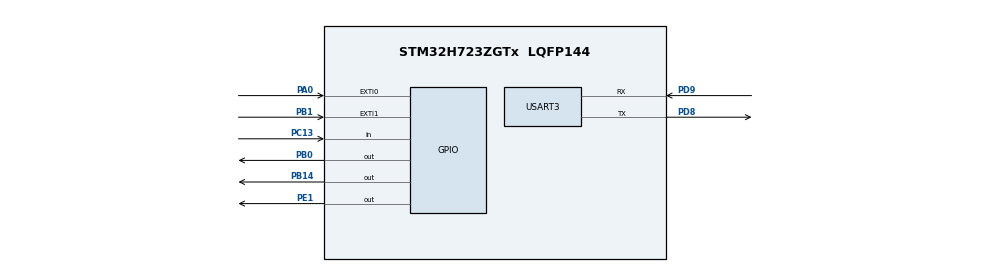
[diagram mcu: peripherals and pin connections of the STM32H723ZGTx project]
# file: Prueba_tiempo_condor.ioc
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CORTEX_M7.default_mode_Activation=1
Mcu.Family=STM32H7
Mcu.Name=STM32H723ZGTx
Mcu.Package=LQFP144
NUCLEO-H723ZG.BUTTON=1
NUCLEO-H723ZG.LD1=true
NUCLEO-H723ZG.LD2=true
NUCLEO-H723ZG.LD3=true
NUCLEO-H723ZG.VCP=false
NVIC.EXTI15_10_IRQn=true\:0\:0\:false\:false\:true\:false\:true\:true
NVIC.PriorityGroup=NVIC_PRIORITYGROUP_4
PA0.Signal=GPXTI0
PA13(JTMS/SWDIO).GPIO_Label=SWDIO
PA13(JTMS/SWDIO).Signal=DEBUG_JTMS-SWDIO
PA14(JTCK/SWCLK).GPIO_Label=SWCLK
PA14(JTCK/SWCLK).Signal=DEBUG_JTCK-SWCLK
PB0.Signal=GPIO_Output
PB1.Signal=GPXTI1
PB14.Signal=GPIO_Output
PC13.Signal=GPIO_Input
PC14-OSC32_IN.Signal=RCC_OSC32_IN
PC15-OSC32_OUT.Signal=RCC_OSC32_OUT
PD8.Mode=Asynchronous
PD8.Signal=USART3_TX
PD9.Mode=Asynchronous
PD9.Signal=USART3_RX
PE1.Signal=GPIO_Output
ProjectManager.HeapSize=0x200
ProjectManager.StackSize=0x400
ProjectManager.TargetToolchain=STM32CubeIDE
RCC.ADCFreq_Value=152000000
RCC.APB1Freq_Value=137500000
RCC.APB2Freq_Value=137500000
RCC.APB3Freq_Value=137500000
RCC.APB4Freq_Value=137500000
RCC.CortexFreq_Value=550000000
RCC.D1PPRE=RCC_APB3_DIV2
RCC.D2PPRE1=RCC_APB1_DIV2
RCC.D2PPRE2=RCC_APB2_DIV2
RCC.D3PPRE=RCC_APB4_DIV2
RCC.DIVM1=8
RCC.DIVM2=1
RCC.DIVN1=275
RCC.DIVN2=19
RCC.DIVP1=1
RCC.DIVQ1=4
RCC.HCLKFreq_Value=275000000
RCC.HPRE=RCC_HCLK_DIV2
RCC.HSE_VALUE=8000000
RCC.HSIDiv=RCC_PLLSAIDIVR_4
RCC.SYSCLKFreq_VALUE=550000000
RCC.SYSCLKSource=RCC_SYSCLKSOURCE_PLLCLK
RCC.USBCLockSelection=RCC_USBCLKSOURCE_HSI48
RCC.USBFreq_Value=48000000
USART3.VirtualMode-Asynchronous=VM_ASYNC
VP_MEMORYMAP_VS_MEMORYMAP.Mode=CurAppReg
VP_NUCLEO-H723ZG_VS_BSP_COMMON.Mode=COMMON
board=NUCLEO-H723ZG

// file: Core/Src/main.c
/* USER CODE BEGIN Header */
/**
  ******************************************************************************
  * @file           : main.c
  * @brief          : Main program body
  ******************************************************************************
  * @attention
  *
  * Copyright (c) 2025 STMicroelectronics.
  * All rights reserved.
  *
  * This software is licensed under terms that can be found in the LICENSE file
  * in the root directory of this software component.
  * If no LICENSE file comes with this software, it is provided AS-IS.
  *
  ******************************************************************************
  */
/* USER CODE END Header */
#include "main.h"

/* USER CODE BEGIN Includes */
#include <stdio.h>
#include <stdlib.h>
/* USER CODE END Includes */

/* USER CODE BEGIN PD */
#define PUTCHAR_PROTOTYPE       int __io_putchar(int ch)
/* USER CODE END PD */

UART_HandleTypeDef huart3;

void SystemClock_Config(void);
static void MPU_Config(void);
static void MX_GPIO_Init(void);
static void MX_USART3_UART_Init(void);

/* USER CODE BEGIN 0 */
void iniciar_DWT(void)
{
	// Habilitar DWT
	CoreDebug->DEMCR |= CoreDebug_DEMCR_TRCENA_Msk;
	DWT->CYCCNT = 0;
	DWT->CTRL |= DWT_CTRL_CYCCNTENA_Msk;
}

// MEDICIÓN DE LOS PRINT (SE PASA EL NÚMERO DE VECES QUE SE QUIERE REALIZAR LA OPERACIÓN COMO PARÁMETRO)
void test_printeo_caracter(uint32_t iteraciones)
{
    volatile uint32_t inicio, fin, ciclos, tiempo_ns;
    volatile uint32_t tiempos[iteraciones];
    volatile uint32_t max_value = 0;
    volatile uint32_t min_value = 4294967295;
    volatile uint32_t sum_value = 0;
    volatile uint32_t tiempo_medio;

    volatile uint32_t counter = 0;

    while (counter < iteraciones)
    {
        DWT->CYCCNT = 0;
        inicio = DWT->CYCCNT;
        printf("a\n");
        fin = DWT->CYCCNT;

        ciclos = fin - inicio;
        tiempo_ns = (ciclos * (1e9f / SystemCoreClock));

        tiempos[counter] = tiempo_ns;

        counter++;
    }

    // Obtener el valor máximo, mínimo y promedio entre todos los tiempos
    for (uint32_t i=0; i<=counter; i++)
    {
        if (tiempos[i] > max_value)
        {
            max_value = tiempos[i];
        }
        if (tiempos[i] < min_value)
        {
            min_value = tiempos[i];
        }

        sum_value += tiempos[i];

    }

    tiempo_medio = sum_value/iteraciones;

    printf("Tiempo promedio printf(): %lu ns\r\n\r\n", tiempo_medio);
    printf("Tiempo máximo printf(): %lu ns\r\n\r\n", max_value);
    printf("Tiempo mínimo printf(): %lu ns\r\n\r\n", min_value);
}

void test_printeo_multiples_caracteres(uint32_t iteraciones)
{
    volatile uint32_t inicio, fin, ciclos, tiempo_ns;
    volatile uint32_t tiempos[iteraciones];
    volatile uint32_t max_value = 0;
    volatile uint32_t min_value = 4294967295;
    volatile uint32_t sum_value = 0;
    volatile uint32_t tiempo_medio;

    volatile uint32_t counter = 0;

    while (counter < iteraciones)
    {
        DWT->CYCCNT = 0;
        inicio = DWT->CYCCNT;
        printf("[TEST] Printf simple.\n");
        fin = DWT->CYCCNT;

        ciclos = fin - inicio;
        tiempo_ns = (ciclos * (1e9f / SystemCoreClock));

        tiempos[counter] = tiempo_ns;

        counter++;
    }

    for (uint32_t i=0; i<=counter; i++)
    {
        if (tiempos[i] > max_value)
        {
            max_value = tiempos[i];
        }
        if (tiempos[i] < min_value)
        {
            min_value = tiempos[i];
        }

        sum_value += tiempos[i];

    }

    tiempo_medio = sum_value/iteraciones;

    printf("Tiempo promedio printf() múltiples caractéres: %lu ns\r\n\r\n", tiempo_medio);
    printf("Tiempo máximo printf() múltiples caractéres: %lu ns\r\n\r\n", max_value);
    printf("Tiempo mínimo printf() múltiples caractéres: %lu ns\r\n\r\n", min_value);
}

// MEDICIÓN DE LAS ASIGNACIONES SIMPLES
void test_asignaciones_8bits(uint32_t iteraciones)
{
    volatile uint32_t inicio, fin, ciclos, tiempo_ns;
    volatile uint32_t tiempos[iteraciones];
    volatile uint32_t max_value = 0;
    volatile uint32_t min_value = 4294967295;
    volatile uint32_t sum_value = 0;
    volatile uint32_t tiempo_medio;

    volatile uint32_t counter = 0;

    volatile uint8_t asignacion;

    while (counter < iteraciones)
    {
        DWT->CYCCNT = 0;
        inicio = DWT->CYCCNT;
        asignacion = rand() & 0xFF;
        fin = DWT->CYCCNT;

        ciclos = fin - inicio;
        tiempo_ns = (ciclos * (1e9f / SystemCoreClock));

        tiempos[counter] = tiempo_ns;

        counter++;
    }

    for (uint32_t i=0; i<=counter; i++)
    {
        if (tiempos[i] > max_value)
        {
            max_value = tiempos[i];
        }
        if (tiempos[i] < min_value)
        {
            min_value = tiempos[i];
        }

        sum_value += tiempos[i];

    }

    tiempo_medio = sum_value/iteraciones;

    printf("Tiempo promedio asignación 8bits: %lu ns\r\n\r\n", tiempo_medio);
    printf("Tiempo máximo asignación 8bits: %lu ns\r\n\r\n", max_value);
    printf("Tiempo mínimo asignación 8bits: %lu ns\r\n\r\n", min_value);

}

void test_asignaciones_16bits(uint32_t iteraciones)
{
    volatile uint32_t inicio, fin, ciclos, tiempo_ns;
    volatile uint32_t tiempos[iteraciones];
    volatile uint32_t max_value = 0;
    volatile uint32_t min_value = 4294967295;
    volatile uint32_t sum_value = 0;
    volatile uint32_t tiempo_medio;

    volatile uint32_t counter = 0;

    volatile uint16_t asignacion;

    while (counter < iteraciones)
    {
        DWT->CYCCNT = 0;
        inicio = DWT->CYCCNT;
        asignacion = rand() & 0xFFFF;
        fin = DWT->CYCCNT;

        ciclos = fin - inicio;
        tiempo_ns = (ciclos * (1e9f / SystemCoreClock));

        tiempos[counter] = tiempo_ns;

        counter++;
    }

    for (uint32_t i=0; i<=counter; i++)
    {
        if (tiempos[i] > max_value)
        {
            max_value = tiempos[i];
        }
        if (tiempos[i] < min_value)
        {
            min_value = tiempos[i];
        }

        sum_value += tiempos[i];

    }

    tiempo_medio = sum_value/iteraciones;

    printf("Tiempo promedio asignación 16bits: %lu ns\r\n\r\n", tiempo_medio);
    printf("Tiempo máximo asignación 16bits: %lu ns\r\n\r\n", max_value);
    printf("Tiempo mínimo asignación 16bits: %lu ns\r\n\r\n", min_value);

}

void test_asignaciones_32bits(uint32_t iteraciones)
{
    volatile uint32_t inicio, fin, ciclos, tiempo_ns;
    volatile uint32_t tiempos[iteraciones];
    volatile uint32_t max_value = 0;
    volatile uint32_t min_value = 4294967295;
    volatile uint32_t sum_value = 0;
    volatile uint32_t tiempo_medio;

    volatile uint32_t counter = 0;

    volatile uint32_t asignacion;

    while (counter < iteraciones)
    {
        DWT->CYCCNT = 0;
        inicio = DWT->CYCCNT;
        asignacion = ((uint32_t)rand() << 16) | (uint32_t)rand();
        fin = DWT->CYCCNT;

        ciclos = fin - inicio;
        tiempo_ns = (ciclos * (1e9f / SystemCoreClock));

        tiempos[counter] = tiempo_ns;

        counter++;
    }

    for (uint32_t i=0; i<=counter; i++)
    {
        if (tiempos[i] > max_value)
        {
            max_value = tiempos[i];
        }
        if (tiempos[i] < min_value)
        {
            min_value = tiempos[i];
        }

        sum_value += tiempos[i];

    }

    tiempo_medio = sum_value/iteraciones;

    printf("Tiempo promedio asignación 32bits: %lu ns\r\n\r\n", tiempo_medio);
    printf("Tiempo máximo asignación 32bits: %lu ns\r\n\r\n", max_value);
    printf("Tiempo mínimo asignación 32bits: %lu ns\r\n\r\n", min_value);

}

// MEDICIÓN DE TIM2
void test_lectura_tim_dos(uint32_t iteraciones)
{
    volatile uint32_t inicio, fin, ciclos, tiempo_ns;
    volatile uint32_t tiempos[iteraciones];
    volatile uint32_t max_value = 0;
    volatile uint32_t min_value = 4294967295;
    volatile uint32_t sum_value = 0;
    volatile uint32_t tiempo_medio;

    volatile uint32_t counter = 0;

    while (counter < iteraciones)
    {
        DWT->CYCCNT = 0;
        inicio = DWT->CYCCNT;
        uint32_t t = TIM2->CNT;  // <--- lectura de TIM2
        fin = DWT->CYCCNT;

        ciclos = fin - inicio;
        tiempo_ns = (ciclos * (1e9f / SystemCoreClock));

        tiempos[counter] = tiempo_ns;

        counter++;
    }

    for (uint32_t i=0; i<=counter; i++)
    {
        if (tiempos[i] > max_value)
        {
            max_value = tiempos[i];
        }
        if (tiempos[i] < min_value)
        {
            min_value = tiempos[i];
        }

        sum_value += tiempos[i];

    }

    tiempo_medio = sum_value/iteraciones;

    printf("Tiempo promedio lectura TIM2: %lu ns\r\n\r\n", tiempo_medio);
    printf("Tiempo máximo lectura TIM2: %lu ns\r\n\r\n", max_value);
    printf("Tiempo mínimo lectura TIM2: %lu ns\r\n\r\n", min_value);

}

// MEDICIÓN SWITCH CASE
void test_switch(uint32_t iteraciones)
{
    volatile uint32_t inicio, fin, ciclos, tiempo_ns;
    volatile uint32_t tiempos[iteraciones];
    volatile uint32_t max_value = 0;
    volatile uint32_t min_value = 4294967295;
    volatile uint32_t sum_value = 0;
    volatile uint32_t tiempo_medio;

    volatile uint16_t GPIO_Pin = GPIO_PIN_3;
    volatile uint8_t canal = 0;

    volatile uint32_t counter = 0;

    while (counter < iteraciones)
    {
        DWT->CYCCNT = 0;
        inicio = DWT->CYCCNT;
        switch (GPIO_Pin) {
            case GPIO_PIN_1: canal = 1; break;
            case GPIO_PIN_2: canal = 2; break;
            case GPIO_PIN_3: canal = 3; break;
            case GPIO_PIN_4: canal = 4; break;
            default: canal = 99; break;
        }
        fin = DWT->CYCCNT;

        ciclos = fin - inicio;
        tiempo_ns = (ciclos * (1e9f / SystemCoreClock));

        tiempos[counter] = tiempo_ns;

        counter++;
    }

    for (uint32_t i=0; i<=counter; i++)
    {
        if (tiempos[i] > max_value)
        {
            max_value = tiempos[i];
        }
        if (tiempos[i] < min_value)
        {
            min_value = tiempos[i];
        }

        sum_value += tiempos[i];

    }

    tiempo_medio = sum_value/iteraciones;

    printf("Tiempo promedio switch: %lu ns\r\n\r\n", tiempo_medio);
    printf("Tiempo máximo switch: %lu ns\r\n\r\n", max_value);
    printf("Tiempo mínimo switch: %lu ns\r\n\r\n", min_value);
}

// MEDICIÓN DE LA CONDICIÓN IF, el segundo parámetro es el número de condiciones que se quiere probar
void test_if(uint32_t iteraciones, uint8_t condiciones)
{
    volatile uint32_t counter = 0;

    volatile uint32_t a = 0;
    volatile uint32_t b = 1;
    volatile uint32_t c = 1;

    if (condiciones == 1)
    {
        while (counter < iteraciones)
        {
            if (a > b) {
                continue;
            }
            counter++;
        }
    }
    else if (condiciones == 2)
    {
        while (counter < iteraciones)
        {
            if (a > b && c != a) {
                continue;
            }
            counter++;
        }
    }
    else if (condiciones == 3)
    {
        while (counter < iteraciones)
        {
            if (a > b && c != a || a == b) {
                continue;
            }
            counter++;
        }
    }
    else if (condiciones == 4)
    {
        while (counter < iteraciones)
        {
            if (a > b && c != a || a == b && c != b) {
                continue;
            }
            counter++;
        }
    }
}

// Medición de coincidencias
void test_coincidencias(uint32_t iteraciones)
{
    volatile uint32_t inicio, fin, ciclos, tiempo_ns;
    volatile uint32_t tiempos[iteraciones];
    volatile uint32_t max_value = 0;
    volatile uint32_t min_value = 4294967295;
    volatile uint32_t sum_value = 0;
    volatile uint32_t tiempo_medio;

    volatile uint32_t counter = 0;

    uint32_t t1 = 1000;
    uint32_t t2 = 1200;
    uint8_t ch1 = 3;
    uint8_t ch2 = 4;

    while (counter < iteraciones)
    {
        DWT->CYCCNT = 0;
        inicio = DWT->CYCCNT;
        if ( ch1 != ch2 &&
             (t2 - t1) >= 50 &&
             (t2 - t1) <= 800 ) {
            __NOP();
        }
        fin = DWT->CYCCNT;

        ciclos = fin - inicio;
        tiempo_ns = (ciclos * (1e9f / SystemCoreClock));

        tiempos[counter] = tiempo_ns;

        counter++;
    }

    for (uint32_t i=0; i<=counter; i++)
    {
        if (tiempos[i] > max_value)
        {
            max_value = tiempos[i];
        }
        if (tiempos[i] < min_value)
        {
            min_value = tiempos[i];
        }

        sum_value += tiempos[i];

    }

    tiempo_medio = sum_value/iteraciones;

    printf("Tiempo promedio coincidencia: %lu ns\r\n\r\n", tiempo_medio);
    printf("Tiempo máximo coincidencia: %lu ns\r\n\r\n", max_value);
    printf("Tiempo mínimo coincidencia: %lu ns\r\n\r\n", min_value);
}

void medir_tiempo_ejemplo(void)
{
    // 1) MEDIR TIEMPO DE UN printf()
    test_printeo_caracter(100); // UN SOLO CARACTER
    //test_printeo_multiples_caracteres(100); // MÚLTIPLES CARACTERES

    // 2) MEDIR UNA ASIGNACIÓN SIMPLE
    test_asignaciones_8bits(100); // Probar asignaciones para variables de 8 bits
    //test_asignaciones_16bits(100); // Probar asignaciones para variables de 16 bits
    //test_asignaciones_32bits(100); // Probar asignaciones para variables de 32 bits

    // 3) MEDIR LECTURA DE TIM2->CNT
    test_lectura_tim_dos(100);

    // 4) MEDIR EL switch
    test_switch(100);

    // 5) MEDIR IF Statements con distinto número de condiciones
    test_if(100, 3); // Se pueden probar condicionales de 1 a 4 (segundo parámetro)

    // 6) MEDIR COMPARACIONES DE LAS COINCIDENCIAS
    test_coincidencias(100);

    // RESUMEN
    printf("===========================================\r\n");
    printf(" Medición completada.\r\n");
    printf(" Frecuencia CPU: %lu Hz\r\n", SystemCoreClock);
    printf("===========================================\r\n");
}
/* USER CODE END 0 */

int main(void)
{

  /* MPU Configuration--------------------------------------------------------*/
  MPU_Config();

  /* MCU Configuration--------------------------------------------------------*/

  /* Reset of all peripherals, Initializes the Flash interface and the Systick. */
  HAL_Init();

  /* Configure the system clock */
  SystemClock_Config();

  /* Initialize all configured peripherals */
  MX_GPIO_Init();
  MX_USART3_UART_Init();
  /* USER CODE BEGIN 2 */
  iniciar_DWT();
  printf("\n\n Inicio Medición\r\n");
  medir_tiempo_ejemplo();
  /* USER CODE END 2 */

  /* Initialize leds */
  BSP_LED_Init(LED_GREEN);
  BSP_LED_Init(LED_YELLOW);
  BSP_LED_Init(LED_RED);

  /* Initialize USER push-button, will be used to trigger an interrupt each time it's pressed.*/
  BSP_PB_Init(BUTTON_USER, BUTTON_MODE_EXTI);

  /* Infinite loop */
  while (1)
  {

  }
}

void SystemClock_Config(void)
{
  RCC_OscInitTypeDef RCC_OscInitStruct = {0};
  RCC_ClkInitTypeDef RCC_ClkInitStruct = {0};

  /** Supply configuration update enable
  */
  HAL_PWREx_ConfigSupply(PWR_LDO_SUPPLY);

  /** Configure the main internal regulator output voltage
  */
  __HAL_PWR_VOLTAGESCALING_CONFIG(PWR_REGULATOR_VOLTAGE_SCALE0);

  while(!__HAL_PWR_GET_FLAG(PWR_FLAG_VOSRDY)) {}

  /** Initializes the RCC Oscillators according to the specified parameters
  * in the RCC_OscInitTypeDef structure.
  */
  RCC_OscInitStruct.OscillatorType = RCC_OSCILLATORTYPE_HSI;
  RCC_OscInitStruct.HSIState = RCC_HSI_DIV4;
  RCC_OscInitStruct.HSICalibrationValue = 64;
  RCC_OscInitStruct.PLL.PLLState = RCC_PLL_ON;
  RCC_OscInitStruct.PLL.PLLSource = RCC_PLLSOURCE_HSI;
  RCC_OscInitStruct.PLL.PLLM = 8;
  RCC_OscInitStruct.PLL.PLLN = 275;
  RCC_OscInitStruct.PLL.PLLP = 1;
  RCC_OscInitStruct.PLL.PLLQ = 4;
  RCC_OscInitStruct.PLL.PLLR = 2;
  RCC_OscInitStruct.PLL.PLLRGE = RCC_PLL1VCIRANGE_1;
  RCC_OscInitStruct.PLL.PLLVCOSEL = RCC_PLL1VCOWIDE;
  RCC_OscInitStruct.PLL.PLLFRACN = 0;
  if (HAL_RCC_OscConfig(&RCC_OscInitStruct) != HAL_OK)
  {
    Error_Handler();
  }

  /** Initializes the CPU, AHB and APB buses clocks
  */
  RCC_ClkInitStruct.ClockType = RCC_CLOCKTYPE_HCLK|RCC_CLOCKTYPE_SYSCLK
                              |RCC_CLOCKTYPE_PCLK1|RCC_CLOCKTYPE_PCLK2
                              |RCC_CLOCKTYPE_D3PCLK1|RCC_CLOCKTYPE_D1PCLK1;
  RCC_ClkInitStruct.SYSCLKSource = RCC_SYSCLKSOURCE_PLLCLK;
  RCC_ClkInitStruct.SYSCLKDivider = RCC_SYSCLK_DIV1;
  RCC_ClkInitStruct.AHBCLKDivider = RCC_HCLK_DIV2;
  RCC_ClkInitStruct.APB3CLKDivider = RCC_APB3_DIV2;
  RCC_ClkInitStruct.APB1CLKDivider = RCC_APB1_DIV2;
  RCC_ClkInitStruct.APB2CLKDivider = RCC_APB2_DIV2;
  RCC_ClkInitStruct.APB4CLKDivider = RCC_APB4_DIV2;

  if (HAL_RCC_ClockConfig(&RCC_ClkInitStruct, FLASH_LATENCY_3) != HAL_OK)
  {
    Error_Handler();
  }
}

static void MX_USART3_UART_Init(void)
{

  huart3.Instance = USART3;
  huart3.Init.BaudRate = 115200;
  huart3.Init.WordLength = UART_WORDLENGTH_8B;
  huart3.Init.StopBits = UART_STOPBITS_1;
  huart3.Init.Parity = UART_PARITY_NONE;
  huart3.Init.Mode = UART_MODE_TX_RX;
  huart3.Init.HwFlowCtl = UART_HWCONTROL_NONE;
  huart3.Init.OverSampling = UART_OVERSAMPLING_16;
  huart3.Init.OneBitSampling = UART_ONE_BIT_SAMPLE_DISABLE;
  huart3.Init.ClockPrescaler = UART_PRESCALER_DIV1;
  huart3.AdvancedInit.AdvFeatureInit = UART_ADVFEATURE_NO_INIT;
  if (HAL_UART_Init(&huart3) != HAL_OK)
  {
    Error_Handler();
  }
  if (HAL_UARTEx_SetTxFifoThreshold(&huart3, UART_TXFIFO_THRESHOLD_1_8) != HAL_OK)
  {
    Error_Handler();
  }
  if (HAL_UARTEx_SetRxFifoThreshold(&huart3, UART_RXFIFO_THRESHOLD_1_8) != HAL_OK)
  {
    Error_Handler();
  }
  if (HAL_UARTEx_DisableFifoMode(&huart3) != HAL_OK)
  {
    Error_Handler();
  }

}

static void MX_GPIO_Init(void)
{
  GPIO_InitTypeDef GPIO_InitStruct = {0};

  /* GPIO Ports Clock Enable */
  __HAL_RCC_GPIOC_CLK_ENABLE();
  __HAL_RCC_GPIOA_CLK_ENABLE();
  __HAL_RCC_GPIOB_CLK_ENABLE();
  __HAL_RCC_GPIOD_CLK_ENABLE();

  /*Configure GPIO pin : PA0 */
  GPIO_InitStruct.Pin = GPIO_PIN_0;
  GPIO_InitStruct.Mode = GPIO_MODE_IT_RISING;
  GPIO_InitStruct.Pull = GPIO_NOPULL;
  HAL_GPIO_Init(GPIOA, &GPIO_InitStruct);

  /*Configure GPIO pin : PB1 */
  GPIO_InitStruct.Pin = GPIO_PIN_1;
  GPIO_InitStruct.Mode = GPIO_MODE_IT_RISING;
  GPIO_InitStruct.Pull = GPIO_NOPULL;
  HAL_GPIO_Init(GPIOB, &GPIO_InitStruct);

}

/* USER CODE BEGIN 4 */
/**
  * @brief  Retargets the C library printf function to the USART.
  * None
  * @retval None
  */
PUTCHAR_PROTOTYPE
{
	/* Place your implementation of fputc here */
	/* e.g. write a character to the USART1 and Loop until the end of transmission */
	HAL_UART_Transmit(&huart3, (uint8_t *)&ch, 1, 0xFFFF);

	return ch;
}
/* USER CODE END 4 */

 /* MPU Configuration */

void MPU_Config(void)
{
  MPU_Region_InitTypeDef MPU_InitStruct = {0};

  /* Disables the MPU */
  HAL_MPU_Disable();

  /** Initializes and configures the Region and the memory to be protected
  */
  MPU_InitStruct.Enable = MPU_REGION_ENABLE;
  MPU_InitStruct.Number = MPU_REGION_NUMBER0;
  MPU_InitStruct.BaseAddress = 0x0;
  MPU_InitStruct.Size = MPU_REGION_SIZE_4GB;
  MPU_InitStruct.SubRegionDisable = 0x87;
  MPU_InitStruct.TypeExtField = MPU_TEX_LEVEL0;
  MPU_InitStruct.AccessPermission = MPU_REGION_NO_ACCESS;
  MPU_InitStruct.DisableExec = MPU_INSTRUCTION_ACCESS_DISABLE;
  MPU_InitStruct.IsShareable = MPU_ACCESS_SHAREABLE;
  MPU_InitStruct.IsCacheable = MPU_ACCESS_NOT_CACHEABLE;
  MPU_InitStruct.IsBufferable = MPU_ACCESS_NOT_BUFFERABLE;

  HAL_MPU_ConfigRegion(&MPU_InitStruct);
  /* Enables the MPU */
  HAL_MPU_Enable(MPU_PRIVILEGED_DEFAULT);

}

void Error_Handler(void)
{
  __disable_irq();
  while (1)
  {
  }
}
